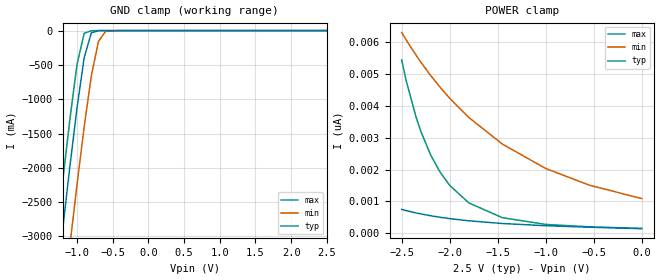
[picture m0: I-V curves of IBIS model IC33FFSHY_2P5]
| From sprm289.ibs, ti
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|   Model IC33FFSHY_2P5
[Model]   IC33FFSHY_2P5
Model_type   Input
Polarity   Non-Inverting
Vinl =   0.7500V
Vinh =   1.7500V
C_comp   2.1510pF   2.1675pF   2.1423pF
[Temperature Range]   25.0000   0.1250k   -40.0000
[Voltage Range]   2.5000V   2.3000V   2.7000V
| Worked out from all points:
|   GND clamp passes 1 mA (typ) near -0.69 V on its own axis
[GND_clamp]
| voltage   I(typ)   I(min)   I(max)
-2.5V     -15.45A    -16.55A    -14.8A
-1.3V     -3.808A    -4.968A    -3.114A
-1.2V     -2.88A     -4.039A    -2.185A
-1.1V     -1.977A    -3.127A    -1.292A
-1V       -1.123A    -2.241A    -489.8mA
-900mV    -393.5mA   -1.402A    -39.28mA
-800mV    -34.06mA   -660.7mA   -2.403mA
-700mV    -1.064mA   -156.4mA   -232.2uA
-600mV    -42.88uA   -13.11mA   -13.27uA
-400mV    -95.51nA   -45.69uA   -11.76nA
2.5V      143.4pA    1.228nA    134.5pA
[POWER_clamp]
| voltage   I(typ)   I(min)   I(max)
-2.5V     747.5pA    6.311nA    5.445nA
-2.45V    708.4pA    6.061nA    4.761nA
-2.35V    638.1pA    5.593nA    3.65nA
-2.3V     606.7pA    5.374nA    3.201nA
-2.2V     550.3pA    4.964nA    2.471nA
-2.1V     501.2pA    4.588nA    1.92nA
-2V       459pA      4.243nA    1.504nA
-1.8V     389.9pA    3.636nA    951pA
-1.45V    304.8pA    2.798nA    487.4pA
-1V       235.8pA    2.034nA    276.4pA
-550mV    189.4pA    1.515nA    200.8pA
0V        143.4pA    1.088nA    150.7pA
